VERSION 5.6 ;
BUSBITCHARS "[]" ;
DIVIDERCHAR "/" ;
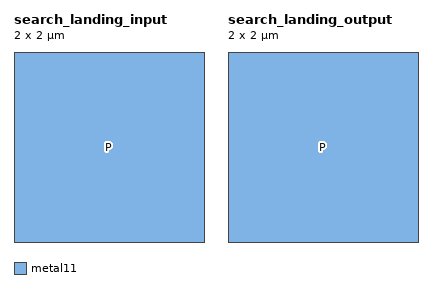
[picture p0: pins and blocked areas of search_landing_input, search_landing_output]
MACRO search_landing_input
 CLASS BLOCK ;
 ORIGIN 0 0 ;
 SIZE 2 BY 2 ;
 PIN P
  DIRECTION INPUT ;
  USE SIGNAL ;
  PORT
   LAYER metal11 ;
   RECT 0 0 2 2 ;
  END
 END P
END search_landing_input
MACRO search_landing_output
 CLASS BLOCK ;
 ORIGIN 0 0 ;
 SIZE 2 BY 2 ;
 PIN P
  DIRECTION OUTPUT ;
  USE SIGNAL ;
  PORT
   LAYER metal11 ;
   RECT 0 0 2 2 ;
  END
 END P
END search_landing_output
END LIBRARY
